VERSION 5.8 ;
BUSBITCHARS "[]" ;
DIVIDERCHAR "/" ;
UNITS
    DATABASE MICRONS 1000 ;
END UNITS

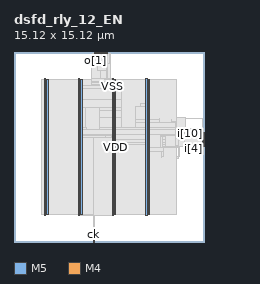
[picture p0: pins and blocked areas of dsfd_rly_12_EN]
MACRO dsfd_rly_12_EN
  FOREIGN dsfd_rly_12_EN 0 0 ;
  CLASS BLOCK ;
  SIZE 15.12 BY 15.12 ;
  PIN ck
    DIRECTION INPUT ;
    USE SIGNAL ;
    PORT
      LAYER M5 ;
        RECT  6.288 0 6.312 0.084 ;
    END
  END ck
  PIN i[0]
    DIRECTION INPUT ;
    USE SIGNAL ;
    PORT
      LAYER M4 ;
        RECT  15.036 7.632 15.12 7.656 ;
    END
  END i[0]
  PIN i[10]
    DIRECTION INPUT ;
    USE SIGNAL ;
    PORT
      LAYER M4 ;
        RECT  15.036 8.592 15.12 8.616 ;
    END
  END i[10]
  PIN i[11]
    DIRECTION INPUT ;
    USE SIGNAL ;
    PORT
      LAYER M4 ;
        RECT  15.036 8.688 15.12 8.712 ;
    END
  END i[11]
  PIN i[1]
    DIRECTION INPUT ;
    USE SIGNAL ;
    PORT
      LAYER M4 ;
        RECT  15.036 7.728 15.12 7.752 ;
    END
  END i[1]
  PIN i[2]
    DIRECTION INPUT ;
    USE SIGNAL ;
    PORT
      LAYER M4 ;
        RECT  15.036 7.824 15.12 7.848 ;
    END
  END i[2]
  PIN i[3]
    DIRECTION INPUT ;
    USE SIGNAL ;
    PORT
      LAYER M4 ;
        RECT  15.036 7.92 15.12 7.944 ;
    END
  END i[3]
  PIN i[4]
    DIRECTION INPUT ;
    USE SIGNAL ;
    PORT
      LAYER M4 ;
        RECT  15.036 8.016 15.12 8.04 ;
    END
  END i[4]
  PIN i[5]
    DIRECTION INPUT ;
    USE SIGNAL ;
    PORT
      LAYER M4 ;
        RECT  15.036 8.112 15.12 8.136 ;
    END
  END i[5]
  PIN i[6]
    DIRECTION INPUT ;
    USE SIGNAL ;
    PORT
      LAYER M4 ;
        RECT  15.036 8.208 15.12 8.232 ;
    END
  END i[6]
  PIN i[7]
    DIRECTION INPUT ;
    USE SIGNAL ;
    PORT
      LAYER M4 ;
        RECT  15.036 8.304 15.12 8.328 ;
    END
  END i[7]
  PIN i[8]
    DIRECTION INPUT ;
    USE SIGNAL ;
    PORT
      LAYER M4 ;
        RECT  15.036 8.4 15.12 8.424 ;
    END
  END i[8]
  PIN i[9]
    DIRECTION INPUT ;
    USE SIGNAL ;
    PORT
      LAYER M4 ;
        RECT  15.036 8.496 15.12 8.52 ;
    END
  END i[9]
  PIN o[0]
    DIRECTION OUTPUT ;
    USE SIGNAL ;
    PORT
      LAYER M5 ;
        RECT  6.384 15.036 6.408 15.12 ;
    END
  END o[0]
  PIN o[10]
    DIRECTION OUTPUT ;
    USE SIGNAL ;
    PORT
      LAYER M5 ;
        RECT  7.344 15.036 7.368 15.12 ;
    END
  END o[10]
  PIN o[11]
    DIRECTION OUTPUT ;
    USE SIGNAL ;
    PORT
      LAYER M5 ;
        RECT  7.44 15.036 7.464 15.12 ;
    END
  END o[11]
  PIN o[1]
    DIRECTION OUTPUT ;
    USE SIGNAL ;
    PORT
      LAYER M5 ;
        RECT  6.48 15.036 6.504 15.12 ;
    END
  END o[1]
  PIN o[2]
    DIRECTION OUTPUT ;
    USE SIGNAL ;
    PORT
      LAYER M5 ;
        RECT  6.576 15.036 6.6 15.12 ;
    END
  END o[2]
  PIN o[3]
    DIRECTION OUTPUT ;
    USE SIGNAL ;
    PORT
      LAYER M5 ;
        RECT  6.672 15.036 6.696 15.12 ;
    END
  END o[3]
  PIN o[4]
    DIRECTION OUTPUT ;
    USE SIGNAL ;
    PORT
      LAYER M5 ;
        RECT  6.768 15.036 6.792 15.12 ;
    END
  END o[4]
  PIN o[5]
    DIRECTION OUTPUT ;
    USE SIGNAL ;
    PORT
      LAYER M5 ;
        RECT  6.864 15.036 6.888 15.12 ;
    END
  END o[5]
  PIN o[6]
    DIRECTION OUTPUT ;
    USE SIGNAL ;
    PORT
      LAYER M5 ;
        RECT  6.96 15.036 6.984 15.12 ;
    END
  END o[6]
  PIN o[7]
    DIRECTION OUTPUT ;
    USE SIGNAL ;
    PORT
      LAYER M5 ;
        RECT  7.056 15.036 7.08 15.12 ;
    END
  END o[7]
  PIN o[8]
    DIRECTION OUTPUT ;
    USE SIGNAL ;
    PORT
      LAYER M5 ;
        RECT  7.152 15.036 7.176 15.12 ;
    END
  END o[8]
  PIN o[9]
    DIRECTION OUTPUT ;
    USE SIGNAL ;
    PORT
      LAYER M5 ;
        RECT  7.248 15.036 7.272 15.12 ;
    END
  END o[9]
  PIN rs
    DIRECTION INPUT ;
    USE SIGNAL ;
    PORT
      LAYER M5 ;
        RECT  6.384 0 6.408 0.084 ;
    END
  END rs
  PIN VDD
    DIRECTION INOUT ;
    USE POWER ;
    PORT
      LAYER M5 ;
        RECT  10.692 2.151 10.812 12.969 ;
        RECT  7.992 2.151 8.112 12.969 ;
        RECT  5.292 2.151 5.412 12.969 ;
        RECT  2.592 2.151 2.712 12.969 ;
    END
  END VDD
  PIN VSS
    DIRECTION INOUT ;
    USE GROUND ;
    PORT
      LAYER M5 ;
        RECT  10.5 2.137 10.62 12.983 ;
        RECT  7.8 2.137 7.92 12.983 ;
        RECT  5.1 2.137 5.22 12.983 ;
        RECT  2.4 2.137 2.52 12.983 ;
    END
  END VSS
  # OT_OBS_CLOSED layer=M5 d_um=1.536 added=4
  OBS
    LAYER RVTN ;
     RECT  2.16 2.16 12.96 2.295 ;
     RECT  2.16 2.565 12.96 2.835 ;
     RECT  2.16 3.105 12.96 3.375 ;
     RECT  2.16 3.645 12.96 3.915 ;
     RECT  2.16 4.185 12.96 4.455 ;
     RECT  2.16 4.725 12.96 4.995 ;
     RECT  2.16 5.265 12.96 5.535 ;
     RECT  2.16 5.805 12.96 6.075 ;
     RECT  2.16 6.345 12.96 6.615 ;
     RECT  2.16 6.885 12.96 7.155 ;
     RECT  2.16 7.425 12.96 7.695 ;
     RECT  2.16 7.965 12.96 8.235 ;
     RECT  2.16 8.505 12.96 8.775 ;
     RECT  2.16 9.045 12.96 9.315 ;
     RECT  2.16 9.585 12.96 9.855 ;
     RECT  2.16 10.125 12.96 10.395 ;
     RECT  2.16 10.665 12.96 10.935 ;
     RECT  2.16 11.205 12.96 11.475 ;
     RECT  2.16 11.745 12.96 12.015 ;
     RECT  2.16 12.285 12.96 12.555 ;
     RECT  2.16 12.825 12.96 12.96 ;
    LAYER RVTP ;
     RECT  2.16 2.295 12.96 2.565 ;
     RECT  2.16 2.835 12.96 3.105 ;
     RECT  2.16 3.375 12.96 3.645 ;
     RECT  2.16 3.915 12.96 4.185 ;
     RECT  2.16 4.455 12.96 4.725 ;
     RECT  2.16 4.995 12.96 5.265 ;
     RECT  2.16 5.535 12.96 5.805 ;
     RECT  2.16 6.075 12.96 6.345 ;
     RECT  2.16 6.615 12.96 6.885 ;
     RECT  2.16 7.155 12.96 7.425 ;
     RECT  2.16 7.695 12.96 7.965 ;
     RECT  2.16 8.235 12.96 8.505 ;
     RECT  2.16 8.775 12.96 9.045 ;
     RECT  2.16 9.315 12.96 9.585 ;
     RECT  2.16 9.855 12.96 10.125 ;
     RECT  2.16 10.395 12.96 10.665 ;
     RECT  2.16 10.935 12.96 11.205 ;
     RECT  2.16 11.475 12.96 11.745 ;
     RECT  2.16 12.015 12.96 12.285 ;
     RECT  2.16 12.555 12.96 12.825 ;
    LAYER M1 ;
     RECT  2.16 2.151 12.96 12.969 ;
    LAYER M2 ;
     RECT  2.16 2.151 12.96 12.969 ;
     RECT  12.96 6.66 13.127 6.84 ;
     RECT  13.127 6.822 13.163 6.84 ;
     RECT  12.96 7.668 13.631 9.918 ;
     RECT  13.631 7.668 13.667 9.846 ;
     RECT  13.667 7.668 13.703 9.036 ;
     RECT  13.703 8.28 13.847 9.036 ;
     RECT  13.847 8.478 14.243 9.036 ;
     RECT  14.243 9.018 14.963 9.036 ;
     RECT  13.667 9.828 15.035 9.846 ;
    LAYER M3 ;
     RECT  6.408 1.723 6.426 2.255 ;
     RECT  2.415 2.143 2.505 2.413 ;
     RECT  5.115 2.143 5.205 2.413 ;
     RECT  7.815 2.143 7.905 2.413 ;
     RECT  10.515 2.143 10.605 2.413 ;
     RECT  6.516 2.371 6.534 5.225 ;
     RECT  6.408 5.341 6.426 6.781 ;
     RECT  11.7 6.691 11.718 6.781 ;
     RECT  13.104 6.655 13.122 6.817 ;
     RECT  6.408 6.781 6.534 6.845 ;
     RECT  10.515 2.413 10.797 7.231 ;
     RECT  11.7 6.781 11.862 7.231 ;
     RECT  7.815 2.413 8.097 7.429 ;
     RECT  9.036 7.465 9.054 7.501 ;
     RECT  10.515 7.231 11.862 7.501 ;
     RECT  13.104 6.817 13.158 7.501 ;
     RECT  10.515 7.501 13.158 7.619 ;
     RECT  12.816 7.619 13.158 7.663 ;
     RECT  5.115 2.413 5.397 7.699 ;
     RECT  6.444 6.845 6.534 7.699 ;
     RECT  10.515 7.619 12.078 7.735 ;
     RECT  5.115 7.699 6.534 7.771 ;
     RECT  7.38 7.429 8.097 7.771 ;
     RECT  9 7.501 9.054 7.771 ;
     RECT  10.404 7.735 12.078 7.771 ;
     RECT  5.115 7.771 6.57 7.897 ;
     RECT  7.38 7.771 8.154 7.897 ;
     RECT  9 7.771 12.078 7.897 ;
     RECT  12.816 7.663 13.698 8.203 ;
     RECT  12.816 8.203 13.842 8.395 ;
     RECT  14.94 8.107 14.958 8.395 ;
     RECT  5.115 7.897 12.078 8.473 ;
     RECT  12.816 8.395 14.958 8.473 ;
     RECT  5.115 8.473 14.958 8.491 ;
     RECT  5.115 8.491 15.03 8.501 ;
     RECT  5.115 8.501 13.662 8.537 ;
     RECT  5.115 8.537 12.834 8.969 ;
     RECT  14.94 8.501 15.03 9.041 ;
     RECT  6.84 8.969 12.834 9.077 ;
     RECT  5.115 8.969 5.778 9.149 ;
     RECT  9.648 9.077 12.834 9.509 ;
     RECT  12.528 9.509 12.834 9.581 ;
     RECT  13.608 8.537 13.662 9.653 ;
     RECT  9.648 9.509 11.574 9.779 ;
     RECT  12.528 9.581 12.546 9.779 ;
     RECT  11.556 9.779 11.574 9.851 ;
     RECT  15.012 9.041 15.03 9.851 ;
     RECT  13.608 9.653 13.626 9.923 ;
     RECT  6.84 9.077 8.55 9.931 ;
     RECT  6.84 9.931 8.586 10.435 ;
     RECT  6.768 10.435 8.586 10.669 ;
     RECT  5.115 9.149 5.67 10.741 ;
     RECT  6.408 10.669 8.586 10.741 ;
     RECT  9.648 9.779 10.797 10.769 ;
     RECT  10.044 10.769 10.797 11.039 ;
     RECT  5.115 10.741 8.586 11.309 ;
     RECT  5.115 11.309 8.55 12.209 ;
     RECT  5.115 12.209 8.298 12.479 ;
     RECT  6.192 12.479 8.154 12.515 ;
     RECT  2.415 2.413 2.697 12.707 ;
     RECT  5.115 12.479 5.397 12.707 ;
     RECT  6.192 12.515 8.097 12.707 ;
     RECT  10.515 11.039 10.797 12.707 ;
     RECT  6.192 12.707 7.974 12.749 ;
     RECT  2.415 12.707 2.505 12.977 ;
     RECT  5.115 12.707 5.205 12.977 ;
     RECT  6.192 12.749 7.905 12.977 ;
     RECT  10.515 12.707 10.605 12.977 ;
     RECT  6.192 12.977 7.686 14.285 ;
     RECT  6.228 14.285 7.686 15.005 ;
    LAYER M4 ;
     RECT  2.408 2.148 2.512 12.972 ;
     RECT  2.512 2.418 2.704 12.702 ;
     RECT  5.108 2.148 5.212 12.972 ;
     RECT  5.212 2.418 5.404 12.702 ;
     RECT  6.181 14.256 6.217 14.28 ;
     RECT  6.217 14.256 6.353 15 ;
     RECT  6.353 1.728 6.437 1.752 ;
     RECT  6.353 14.208 6.649 15 ;
     RECT  6.649 13.632 6.853 15 ;
     RECT  6.853 13.056 6.929 15 ;
     RECT  6.929 13.008 7.193 15 ;
     RECT  7.193 13.008 7.237 13.08 ;
     RECT  5.404 8.064 7.297 8.28 ;
     RECT  7.237 12.96 7.409 13.08 ;
     RECT  7.193 14.208 7.625 15 ;
     RECT  7.625 14.976 7.697 15 ;
     RECT  7.297 8.064 7.729 8.472 ;
     RECT  7.729 8.064 7.808 8.568 ;
     RECT  7.409 12.96 7.808 12.972 ;
     RECT  7.808 2.148 7.912 12.972 ;
     RECT  7.912 2.418 8.104 12.702 ;
     RECT  8.104 8.16 10.508 8.568 ;
     RECT  10.508 2.148 10.612 12.972 ;
     RECT  10.612 2.418 10.804 12.702 ;
     RECT  10.804 7.536 11.621 8.568 ;
     RECT  11.621 7.536 11.837 8.424 ;
     RECT  11.837 8.16 12.017 8.424 ;
     RECT  12.017 8.16 12.053 8.184 ;
     RECT  13.057 8.016 13.093 8.04 ;
     RECT  13.093 7.632 13.561 8.04 ;
     RECT  13.561 7.632 13.597 8.328 ;
     RECT  13.597 7.632 15.084 8.712 ;
    LAYER M5 ;
     RECT  6.288 0.016 6.408 1.763 ;
     RECT  2.4 2.137 2.52 2.151 ;
     RECT  5.1 2.137 5.22 2.151 ;
     RECT  6.288 1.763 6.312 2.151 ;
     RECT  7.8 2.137 7.92 2.151 ;
     RECT  10.5 2.137 10.62 2.151 ;
     RECT  5.1 2.151 6.312 8.291 ;
     RECT  7.8 2.151 8.112 12.949 ;
     RECT  2.4 2.151 2.712 12.969 ;
     RECT  5.1 8.291 5.412 12.969 ;
     RECT  7.248 12.949 8.112 12.969 ;
     RECT  10.5 2.151 10.812 12.969 ;
     RECT  2.4 12.969 2.52 12.983 ;
     RECT  5.1 12.969 5.22 12.983 ;
     RECT  7.248 12.969 7.92 12.983 ;
     RECT  10.5 12.969 10.62 12.983 ;
     RECT  7.248 12.983 7.368 12.997 ;
     RECT  6.96 12.997 7.368 13.045 ;
     RECT  6.864 13.045 7.368 13.621 ;
     RECT  6.672 13.621 7.368 14.197 ;
     RECT  6.384 14.197 7.464 15.056 ;
     RECT  6.312 1.763 6.408 2.137 ;
     RECT  5.22 2.137 6.288 2.151 ;
     RECT  6.312 2.137 7.8 8.291 ;
     RECT  7.368 12.983 7.464 14.197 ;
  END
END dsfd_rly_12_EN
END LIBRARY
